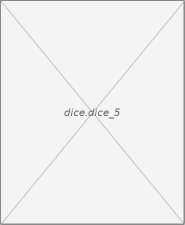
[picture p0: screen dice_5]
VISUALIZATION dice_5  // 185x225
VAR_IN_OUT
VAR_IN_OUT
	
END_VAR
    Image (0,0 185x225), image: dice.dice_5
END_VISUALIZATION
